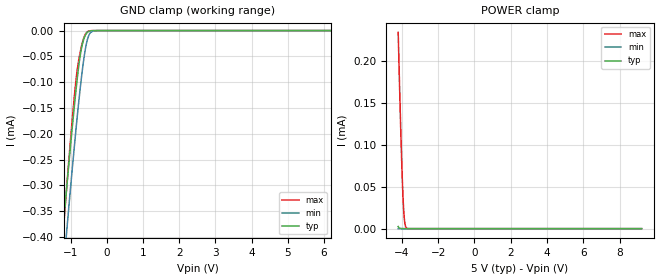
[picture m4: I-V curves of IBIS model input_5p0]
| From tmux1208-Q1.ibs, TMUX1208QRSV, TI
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|   input_5p0 Model
[Model]   input_5p0
Model_type   Input
Vinl = 0.87
Vinh = 1.49
|   typ   min   max
C_comp   2.05894E-15  2.03069E-15  2.13619E-15
| Where Nom  PVT is Nominal Process, 5.0V, 25C
|   Fast PVT is Strong Process,  5.5V, -40C
|   Slow PVT is Weak Process,   4.5V, 125C
[Voltage Range]   5   4.5   5.5
|Junction Temperature
[Temperature Range]   25   125   -40
[Power Clamp Reference]   5   4.5   5.5
[GND Clamp Reference]   0   0   0
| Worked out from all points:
|   GND clamp passes 1 mA (typ) near -1.96 V on its own axis
[GND Clamp]
|   Voltage   I(typ)   I(min)   I(max)
-4.2V     -2.949mA   -3.197mA   -3.357mA
-1.212V   -382.3uA   -470.5uA   -393.3uA
-1.118V   -308.4uA   -393.7uA   -308.2uA
-957.2mV  -186.5uA   -266.9uA   -170.9uA
-823.2mV  -94.65uA   -168.4uA   -77.18uA
-742.8mV  -50.33uA   -114.5uA   -43.25uA
-675.8mV  -25.5uA    -74.37uA   -22.72uA
-595.4mV  -8.863uA   -35.5uA    -7.075uA
-515mV    -2.096uA   -11.84uA   -1.299uA
-448mV    -487.9nA   -3.507uA   -218.5nA
-273.8mV  -1.299nA   -73.05nA   0A
9.2V      0A         0A         0A
[POWER Clamp]
|   Voltage   I(typ)   I(min)   I(max)
-4.2V     2.562uA    18.93nA    234.7uA
-4.12V    569.9nA    4.548nA    166.2uA
-4.053V   156.6nA    1.223nA    113.2uA
-3.999V   54.51nA    138.2pA    75.06uA
-3.972V   31.71nA    0A         58.11uA
-3.945V   18.11nA    0A         43.04uA
-3.919V   9.998nA    0A         30.21uA
-3.892V   5.166nA    0A         19.96uA
-3.852V   1.325nA    0A         9.544uA
-3.811V   0A         0A         4.06uA
-3.744V   0A         0A         844.1nA
9.2V      0A         0A         0A
